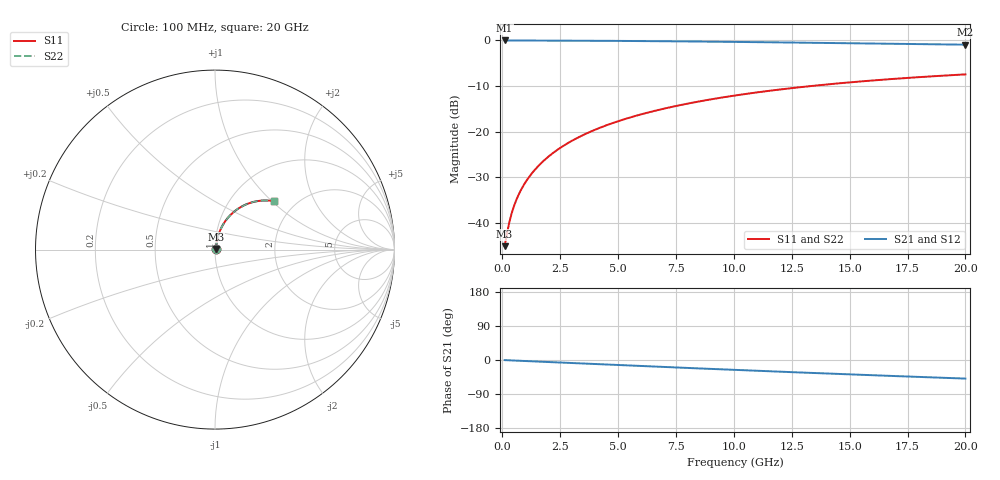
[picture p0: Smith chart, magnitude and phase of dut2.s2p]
! Touchstone file exported from HFSS 2026.1.0
!  File:  C:/ffzhzh/LocalFiles/Ansys_Project_Files/temp_test_TMRDL_2_1782906788_13352.aedt
!  Generated:  07:54:31 PM Jul  1, 2026
!  Design:  TMRDL
!  Project:  temp_test_TMRDL_2_1782906788_13352
! Variables:
!  h_bsmrdl = 2um
!  h_ox = 20um
!  h_rdl = 5um
!  h_sub = 80um
!  h_tmrdl = 2.11um
!  h_tsv = 80um
!  h_via = 3um
!  l_bsmrdl = 300um
!  l_sub = 1123.28um
!  l_tmrdl = 723.28um
!  m_sub = 200um
!  pitch = 54.77um
!  r_tsv = 6um
!  s_tmrdl = 10um
!  w_bsmrdl = 18um
!  w_sub = 500um
!  w_tmrdl = 27.58um
!  x_tsv_center1 = 737.07um
!  x_tsv_center2 = 1055.07um
!  x_tsv_center3 = 1805.93um
!  x_tsv_center4 = 2123.93um
!  x_tsv_center5 = 2874.79um
!  x_tsv_center6 = 3192.79um
# GHz S MA R 50.000000
! Terminal data exported
! Port[1] = TM_RDL1_1_T1
! Port[2] = TM_RDL1_1_T2
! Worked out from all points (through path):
!   200 points, 100 MHz to 20 GHz, reference 50 ohm
!   highest |S21| = -0.04 dB at 100 MHz (marker M1); lowest = -1.0 dB at 20 GHz (marker M2)
!   group delay of S21, straight-line fit = 6.83 ps
!   lowest |S11| = -45.0 dB at 100 MHz (marker M3), VSWR 1.01, Z = 50.5 + j0.299 ohm
!   |S11| at or under -10 dB: start of sweep to 13.35 GHz
!   |S22| runs from -45.0 to -7.5 dB; largest |S21 - S12| = 2.6e-15
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0.1  0.005614 31.8  0.9952 -0.3  0.9952 -0.3  0.005614 31.8
! Gamma 0 0 0 0
! Port Impedance 50 0 50 0
0.2  0.007683 49.7  0.9951 -0.6  0.9951 -0.6  0.007683 49.7
0.3  0.01014 58.9  0.9948 -0.8  0.9948 -0.8  0.01014 58.9
0.4  0.0127 64.0  0.9946 -1.1  0.9946 -1.1  0.0127 64.0
0.5  0.01527 67.3  0.9943 -1.4  0.9943 -1.4  0.01527 67.3
0.6  0.01783 69.6  0.9941 -1.7  0.9941 -1.7  0.01783 69.6
0.8  0.02293 72.6  0.9937 -2.2  0.9937 -2.2  0.02293 72.6
1.1  0.03056 75.1  0.9933 -3.0  0.9933 -3.0  0.03056 75.1
1.3  0.03567 76.1  0.993 -3.5  0.993 -3.5  0.03567 76.1
1.6  0.04337 77.0  0.9925 -4.3  0.9925 -4.3  0.04337 77.0
2.1  0.05625 77.5  0.9918 -5.6  0.9918 -5.6  0.05625 77.5
2.7  0.07173 77.3  0.9906 -7.2  0.9906 -7.2  0.07173 77.3
3.5  0.0923 76.4  0.9888 -9.3  0.9888 -9.3  0.09229 76.4
4.2  0.1101 75.1  0.9868 -11.2  0.9868 -11.2  0.1101 75.1
5  0.1303 73.5  0.9842 -13.2  0.9842 -13.2  0.1303 73.5
5.9  0.1526 71.6  0.9808 -15.6  0.9808 -15.6  0.1526 71.6
6.8  0.1745 69.6  0.9769 -17.9  0.9769 -17.9  0.1745 69.6
8.3  0.2099 66.1  0.9696 -21.7  0.9696 -21.7  0.2099 66.1
10.1  0.2501 61.8  0.9596 -26.2  0.9596 -26.2  0.2501 61.8
13.4  0.3173 54.1  0.9388 -34.2  0.9388 -34.2  0.3172 54.1
16.7  0.3751 46.7  0.9167 -41.8  0.9167 -41.8  0.3751 46.7
20  0.4236 39.5  0.895 -49.0  0.895 -49.0  0.4236 39.6
